VERSION 5.7 ;
  NOWIREEXTENSIONATPIN ON ;
  DIVIDERCHAR "/" ;
  BUSBITCHARS "[]" ;
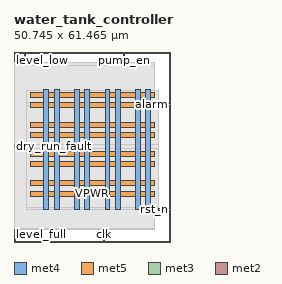
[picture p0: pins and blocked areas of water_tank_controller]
MACRO water_tank_controller
  CLASS BLOCK ;
  FOREIGN water_tank_controller ;
  ORIGIN 0.000 0.000 ;
  SIZE 50.745 BY 61.465 ;
  PIN VGND
    DIRECTION INOUT ;
    USE GROUND ;
    PORT
      LAYER met4 ;
        RECT 12.965 10.640 14.565 49.200 ;
    END
    PORT
      LAYER met4 ;
        RECT 22.855 10.640 24.455 49.200 ;
    END
    PORT
      LAYER met4 ;
        RECT 32.745 10.640 34.345 49.200 ;
    END
    PORT
      LAYER met4 ;
        RECT 42.635 10.640 44.235 49.200 ;
    END
    PORT
      LAYER met5 ;
        RECT 5.280 18.140 45.320 19.740 ;
    END
    PORT
      LAYER met5 ;
        RECT 5.280 27.660 45.320 29.260 ;
    END
    PORT
      LAYER met5 ;
        RECT 5.280 37.180 45.320 38.780 ;
    END
    PORT
      LAYER met5 ;
        RECT 5.280 46.700 45.320 48.300 ;
    END
  END VGND
  PIN VPWR
    DIRECTION INOUT ;
    USE POWER ;
    PORT
      LAYER met4 ;
        RECT 9.665 10.640 11.265 49.200 ;
    END
    PORT
      LAYER met4 ;
        RECT 19.555 10.640 21.155 49.200 ;
    END
    PORT
      LAYER met4 ;
        RECT 29.445 10.640 31.045 49.200 ;
    END
    PORT
      LAYER met4 ;
        RECT 39.335 10.640 40.935 49.200 ;
    END
    PORT
      LAYER met5 ;
        RECT 5.280 14.840 45.320 16.440 ;
    END
    PORT
      LAYER met5 ;
        RECT 5.280 24.360 45.320 25.960 ;
    END
    PORT
      LAYER met5 ;
        RECT 5.280 33.880 45.320 35.480 ;
    END
    PORT
      LAYER met5 ;
        RECT 5.280 43.400 45.320 45.000 ;
    END
  END VPWR
  PIN alarm
    DIRECTION OUTPUT TRISTATE ;
    USE SIGNAL ;
    ANTENNADIFFAREA 0.445500 ;
    PORT
      LAYER met3 ;
        RECT 46.745 44.240 50.745 44.840 ;
    END
  END alarm
  PIN clk
    DIRECTION INPUT ;
    USE SIGNAL ;
    ANTENNAGATEAREA 0.852000 ;
    PORT
      LAYER met2 ;
        RECT 29.070 0.000 29.350 4.000 ;
    END
  END clk
  PIN dry_run_fault
    DIRECTION INPUT ;
    USE SIGNAL ;
    ANTENNAGATEAREA 0.196500 ;
    PORT
      LAYER met3 ;
        RECT 0.000 30.640 4.000 31.240 ;
    END
  END dry_run_fault
  PIN level_full
    DIRECTION INPUT ;
    USE SIGNAL ;
    ANTENNAGATEAREA 0.126000 ;
    PORT
      LAYER met2 ;
        RECT 0.090 0.000 0.370 4.000 ;
    END
  END level_full
  PIN level_low
    DIRECTION INPUT ;
    USE SIGNAL ;
    ANTENNAGATEAREA 0.196500 ;
    PORT
      LAYER met2 ;
        RECT 3.310 57.465 3.590 61.465 ;
    END
  END level_low
  PIN pump_en
    DIRECTION OUTPUT TRISTATE ;
    USE SIGNAL ;
    ANTENNADIFFAREA 0.795200 ;
    PORT
      LAYER met2 ;
        RECT 35.510 57.465 35.790 61.465 ;
    END
  END pump_en
  PIN rst_n
    DIRECTION INPUT ;
    USE SIGNAL ;
    ANTENNAGATEAREA 0.196500 ;
    PORT
      LAYER met3 ;
        RECT 46.745 10.240 50.745 10.840 ;
    END
  END rst_n
  OBS
      LAYER li1 ;
        RECT 5.520 10.795 45.080 49.045 ;
      LAYER met1 ;
        RECT 0.070 10.640 45.470 49.200 ;
      LAYER met2 ;
        RECT 0.100 57.185 3.030 58.210 ;
        RECT 3.870 57.185 35.230 58.210 ;
        RECT 36.070 57.185 45.450 58.210 ;
        RECT 0.100 4.280 45.450 57.185 ;
        RECT 0.650 4.000 28.790 4.280 ;
        RECT 29.630 4.000 45.450 4.280 ;
      LAYER met3 ;
        RECT 4.000 45.240 46.745 49.125 ;
        RECT 4.000 43.840 46.345 45.240 ;
        RECT 4.000 31.640 46.745 43.840 ;
        RECT 4.400 30.240 46.745 31.640 ;
        RECT 4.000 11.240 46.745 30.240 ;
        RECT 4.000 10.375 46.345 11.240 ;
  END
END water_tank_controller
END LIBRARY

